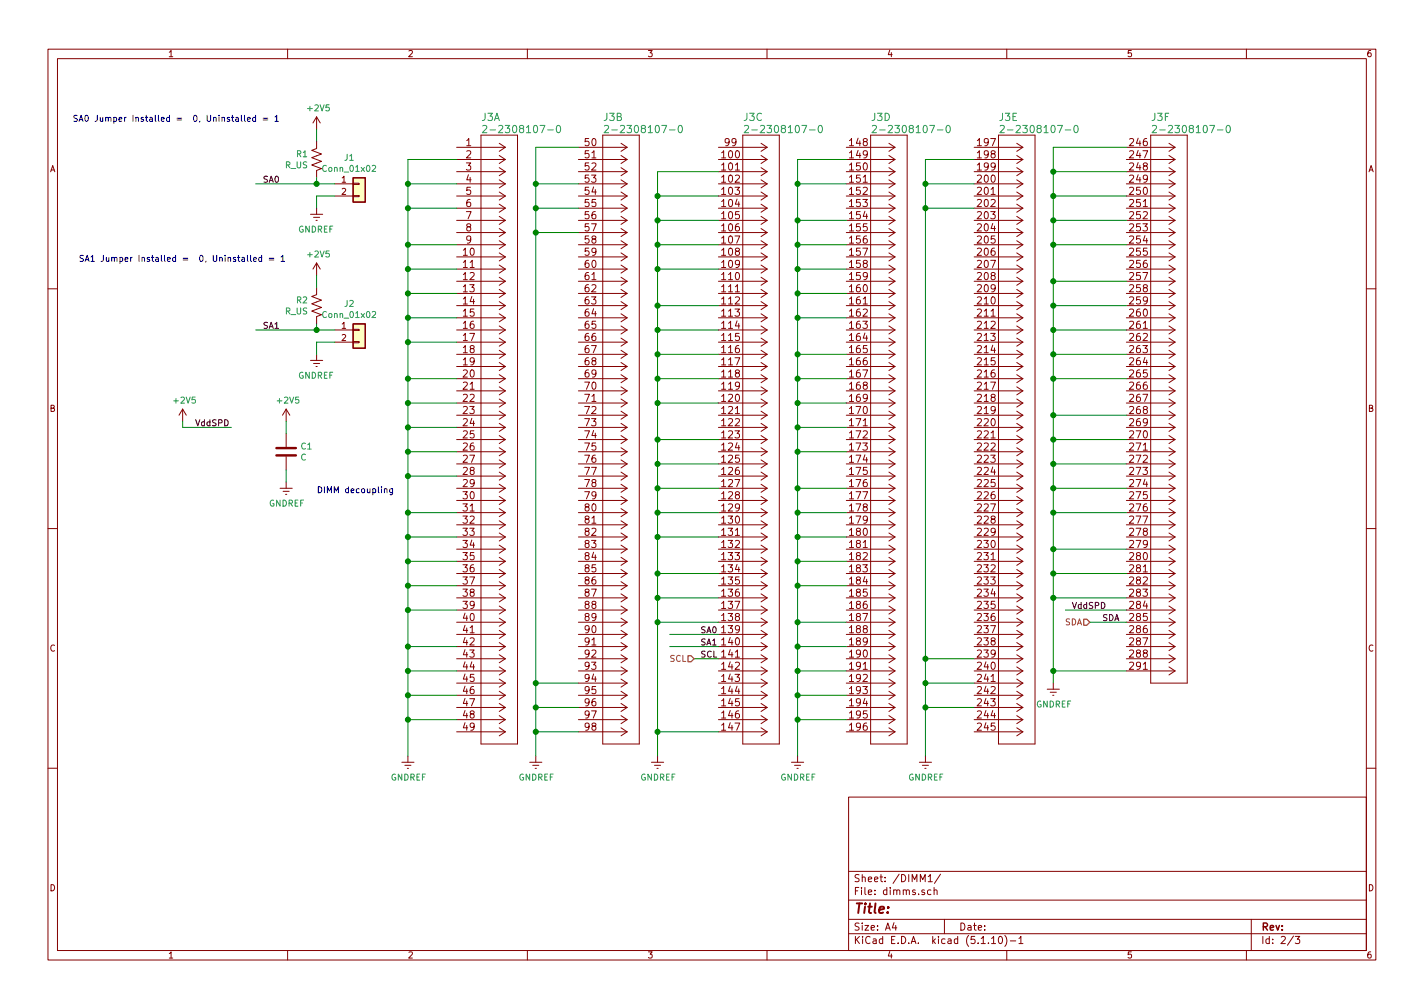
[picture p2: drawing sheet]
<svg xmlns="http://www.w3.org/2000/svg" width="297mm" height="210mm" viewBox="0 0 297 210" stroke-linecap="round" stroke-linejoin="round" font-family="sans-serif">
<defs><g id="words">
<text font-size="2.8" fill="#840000" x="178" y="190.5">Title:</text>
<g font-size="2.1" fill="#008484">
<text x="100.4" y="25.2">J3A</text>
<text x="102.8" y="27.8">2-2308107-0</text>
<text x="125.9" y="25.2">J3B</text>
<text x="128.2" y="27.8">2-2308107-0</text>
<text x="155.1" y="25.2">J3C</text>
<text x="157.4" y="27.8">2-2308107-0</text>
<text x="181.8" y="25.2">J3D</text>
<text x="184.1" y="27.8">2-2308107-0</text>
<text x="208.5" y="25.2">J3E</text>
<text x="210.7" y="27.8">2-2308107-0</text>
<text x="240.2" y="25.2">J3F</text>
<text x="242.5" y="27.8">2-2308107-0</text>
</g>
<g font-size="2.1" fill="#840000">
<text x="97.2" y="30.5">1</text>
<text x="97.2" y="33">2</text>
<text x="97.2" y="35.6">3</text>
<text x="122" y="30.5">50</text>
<text x="122" y="33">51</text>
<text x="122" y="35.6">52</text>
<text x="150.7" y="33">100</text>
<text x="150.7" y="35.6">101</text>
<text x="151.3" y="30.5">99</text>
<text x="177.3" y="30.5">148</text>
<text x="177.3" y="33">149</text>
<text x="177.3" y="35.6">150</text>
<text x="204" y="30.5">197</text>
<text x="204" y="33">198</text>
<text x="204" y="35.6">199</text>
<text x="235.8" y="30.5">246</text>
<text x="235.8" y="33">247</text>
<text x="235.8" y="35.6">248</text>
<text x="97.2" y="38.1">4</text>
<text x="97.2" y="40.6">5</text>
<text x="122" y="38.1">53</text>
<text x="122" y="40.6">54</text>
<text x="150.7" y="38.1">102</text>
<text x="150.7" y="40.6">103</text>
<text x="177.3" y="38.1">151</text>
<text x="177.3" y="40.6">152</text>
<text x="204" y="38.1">200</text>
<text x="204" y="40.6">201</text>
<text x="235.8" y="38.1">249</text>
<text x="235.8" y="40.6">250</text>
<text x="97.2" y="43.2">6</text>
<text x="97.2" y="45.7">7</text>
<text x="122" y="43.2">55</text>
<text x="122" y="45.7">56</text>
<text x="150.7" y="43.2">104</text>
<text x="150.7" y="45.7">105</text>
<text x="177.3" y="43.2">153</text>
<text x="177.3" y="45.7">154</text>
<text x="204" y="43.2">202</text>
<text x="204" y="45.7">203</text>
<text x="235.8" y="43.2">251</text>
<text x="235.8" y="45.7">252</text>
<text x="96.6" y="53.3">10</text>
<text x="97.2" y="48.3">8</text>
<text x="97.2" y="50.8">9</text>
<text x="122" y="48.3">57</text>
<text x="122" y="50.8">58</text>
<text x="122" y="53.3">59</text>
<text x="150.7" y="48.3">106</text>
<text x="150.7" y="50.8">107</text>
<text x="150.7" y="53.3">108</text>
<text x="177.3" y="48.3">155</text>
<text x="177.3" y="50.8">156</text>
<text x="177.3" y="53.3">157</text>
<text x="204" y="48.3">204</text>
<text x="204" y="50.8">205</text>
<text x="204" y="53.3">206</text>
<text x="235.8" y="48.3">253</text>
<text x="235.8" y="50.8">254</text>
<text x="235.8" y="53.3">255</text>
<text x="96.6" y="55.9">11</text>
<text x="96.6" y="58.4">12</text>
<text x="122" y="55.9">60</text>
<text x="122" y="58.4">61</text>
<text x="150.7" y="55.9">109</text>
<text x="150.7" y="58.4">110</text>
<text x="177.3" y="55.9">158</text>
<text x="177.3" y="58.4">159</text>
<text x="204" y="55.9">207</text>
<text x="204" y="58.4">208</text>
<text x="235.8" y="55.9">256</text>
<text x="235.8" y="58.4">257</text>
<text x="96.6" y="61">13</text>
<text x="96.6" y="63.5">14</text>
<text x="122" y="61">62</text>
<text x="122" y="63.5">63</text>
<text x="150.7" y="61">111</text>
<text x="150.7" y="63.5">112</text>
<text x="177.3" y="61">160</text>
<text x="177.3" y="63.5">161</text>
<text x="204" y="61">209</text>
<text x="204" y="63.5">210</text>
<text x="235.8" y="61">258</text>
<text x="235.8" y="63.5">259</text>
<text x="96.6" y="66">15</text>
<text x="96.6" y="68.6">16</text>
<text x="96.6" y="71.1">17</text>
<text x="122" y="66">64</text>
<text x="122" y="68.6">65</text>
<text x="122" y="71.1">66</text>
<text x="150.7" y="66">113</text>
<text x="150.7" y="68.6">114</text>
<text x="150.7" y="71.1">115</text>
<text x="177.3" y="66">162</text>
<text x="177.3" y="68.6">163</text>
<text x="177.3" y="71.1">164</text>
<text x="204" y="66">211</text>
<text x="204" y="68.6">212</text>
<text x="204" y="71.1">213</text>
<text x="235.8" y="66">260</text>
<text x="235.8" y="68.6">261</text>
<text x="235.8" y="71.1">262</text>
<text x="96.6" y="73.7">18</text>
<text x="96.6" y="76.2">19</text>
<text x="122" y="73.7">67</text>
<text x="122" y="76.2">68</text>
<text x="150.7" y="73.7">116</text>
<text x="150.7" y="76.2">117</text>
<text x="177.3" y="73.7">165</text>
<text x="177.3" y="76.2">166</text>
<text x="204" y="73.7">214</text>
<text x="204" y="76.2">215</text>
<text x="235.8" y="73.7">263</text>
<text x="235.8" y="76.2">264</text>
<text x="96.6" y="78.7">20</text>
<text x="96.6" y="81.3">21</text>
<text x="96.6" y="83.8">22</text>
<text x="122" y="78.7">69</text>
<text x="122" y="81.3">70</text>
<text x="122" y="83.8">71</text>
<text x="150.7" y="78.7">118</text>
<text x="150.7" y="81.3">119</text>
<text x="150.7" y="83.8">120</text>
<text x="177.3" y="78.7">167</text>
<text x="177.3" y="81.3">168</text>
<text x="177.3" y="83.8">169</text>
<text x="204" y="78.7">216</text>
<text x="204" y="81.3">217</text>
<text x="204" y="83.8">218</text>
<text x="235.8" y="78.7">265</text>
<text x="235.8" y="81.3">266</text>
<text x="235.8" y="83.8">267</text>
<text x="96.6" y="86.4">23</text>
<text x="96.6" y="88.9">24</text>
<text x="122" y="86.4">72</text>
<text x="122" y="88.9">73</text>
<text x="150.7" y="86.4">121</text>
<text x="150.7" y="88.9">122</text>
<text x="177.3" y="86.4">170</text>
<text x="177.3" y="88.9">171</text>
<text x="204" y="86.4">219</text>
<text x="204" y="88.9">220</text>
<text x="235.8" y="86.4">268</text>
<text x="235.8" y="88.9">269</text>
<text x="96.6" y="91.4">25</text>
<text x="96.6" y="94">26</text>
<text x="122" y="91.4">74</text>
<text x="122" y="94">75</text>
<text x="150.7" y="91.4">123</text>
<text x="150.7" y="94">124</text>
<text x="177.3" y="91.4">172</text>
<text x="177.3" y="94">173</text>
<text x="204" y="91.4">221</text>
<text x="204" y="94">222</text>
<text x="235.8" y="91.4">270</text>
<text x="235.8" y="94">271</text>
<text x="96.6" y="96.5">27</text>
<text x="96.6" y="99.1">28</text>
<text x="96.6" y="101.6">29</text>
<text x="122" y="96.5">76</text>
<text x="122" y="99.1">77</text>
<text x="122" y="101.6">78</text>
<text x="150.7" y="96.5">125</text>
<text x="150.7" y="99.1">126</text>
<text x="150.7" y="101.6">127</text>
<text x="177.3" y="96.5">174</text>
<text x="177.3" y="99.1">175</text>
<text x="177.3" y="101.6">176</text>
<text x="204" y="96.5">223</text>
<text x="204" y="99.1">224</text>
<text x="204" y="101.6">225</text>
<text x="235.8" y="96.5">272</text>
<text x="235.8" y="99.1">273</text>
<text x="235.8" y="101.6">274</text>
<text x="96.6" y="104.1">30</text>
<text x="96.6" y="106.7">31</text>
<text x="122" y="104.1">79</text>
<text x="122" y="106.7">80</text>
<text x="150.7" y="104.1">128</text>
<text x="150.7" y="106.7">129</text>
<text x="177.3" y="104.1">177</text>
<text x="177.3" y="106.7">178</text>
<text x="204" y="104.1">226</text>
<text x="204" y="106.7">227</text>
<text x="235.8" y="104.1">275</text>
<text x="235.8" y="106.7">276</text>
<text x="96.6" y="109.2">32</text>
<text x="96.6" y="111.8">33</text>
<text x="122" y="109.2">81</text>
<text x="122" y="111.8">82</text>
<text x="150.7" y="109.2">130</text>
<text x="150.7" y="111.8">131</text>
<text x="177.3" y="109.2">179</text>
<text x="177.3" y="111.8">180</text>
<text x="204" y="109.2">228</text>
<text x="204" y="111.8">229</text>
<text x="235.8" y="109.2">277</text>
<text x="235.8" y="111.8">278</text>
<text x="96.6" y="114.3">34</text>
<text x="96.6" y="116.8">35</text>
<text x="96.6" y="119.4">36</text>
<text x="122" y="114.3">83</text>
<text x="122" y="116.8">84</text>
<text x="122" y="119.4">85</text>
<text x="150.7" y="114.3">132</text>
<text x="150.7" y="116.8">133</text>
<text x="150.7" y="119.4">134</text>
<text x="177.3" y="114.3">181</text>
<text x="177.3" y="116.8">182</text>
<text x="177.3" y="119.4">183</text>
<text x="204" y="114.3">230</text>
<text x="204" y="116.8">231</text>
<text x="204" y="119.4">232</text>
<text x="235.8" y="114.3">279</text>
<text x="235.8" y="116.8">280</text>
<text x="235.8" y="119.4">281</text>
<text x="96.6" y="121.9">37</text>
<text x="96.6" y="124.5">38</text>
<text x="122" y="121.9">86</text>
<text x="122" y="124.5">87</text>
<text x="150.7" y="121.9">135</text>
<text x="150.7" y="124.5">136</text>
<text x="177.3" y="121.9">184</text>
<text x="177.3" y="124.5">185</text>
<text x="204" y="121.9">233</text>
<text x="204" y="124.5">234</text>
<text x="235.8" y="121.9">282</text>
<text x="235.8" y="124.5">283</text>
<text x="96.6" y="127">39</text>
<text x="96.6" y="129.5">40</text>
<text x="122" y="127">88</text>
<text x="122" y="129.5">89</text>
<text x="150.7" y="127">137</text>
<text x="150.7" y="129.5">138</text>
<text x="177.3" y="127">186</text>
<text x="177.3" y="129.5">187</text>
<text x="204" y="127">235</text>
<text x="204" y="129.5">236</text>
<text x="235.8" y="127">284</text>
<text x="235.8" y="129.5">285</text>
<text x="96.6" y="132.1">41</text>
<text x="96.6" y="134.6">42</text>
<text x="96.6" y="137.2">43</text>
<text x="122" y="132.1">90</text>
<text x="122" y="134.6">91</text>
<text x="122" y="137.2">92</text>
<text x="150.7" y="132.1">139</text>
<text x="150.7" y="134.6">140</text>
<text x="150.7" y="137.2">141</text>
<text x="177.3" y="132.1">188</text>
<text x="177.3" y="134.6">189</text>
<text x="177.3" y="137.2">190</text>
<text x="204" y="132.1">237</text>
<text x="204" y="134.6">238</text>
<text x="204" y="137.2">239</text>
<text x="235.8" y="132.1">286</text>
<text x="235.8" y="134.6">287</text>
<text x="235.8" y="137.2">288</text>
<text x="96.6" y="139.7">44</text>
<text x="96.6" y="142.2">45</text>
<text x="122" y="139.7">93</text>
<text x="122" y="142.2">94</text>
<text x="150.7" y="139.7">142</text>
<text x="150.7" y="142.2">143</text>
<text x="177.3" y="139.7">191</text>
<text x="177.3" y="142.2">192</text>
<text x="204" y="139.7">240</text>
<text x="204" y="142.2">241</text>
<text x="235.8" y="139.7">291</text>
<text x="96.6" y="144.8">46</text>
<text x="96.6" y="147.3">47</text>
<text x="96.6" y="149.9">48</text>
<text x="122" y="144.8">95</text>
<text x="122" y="147.3">96</text>
<text x="122" y="149.9">97</text>
<text x="150.7" y="144.8">144</text>
<text x="150.7" y="147.3">145</text>
<text x="150.7" y="149.9">146</text>
<text x="177.3" y="144.8">193</text>
<text x="177.3" y="147.3">194</text>
<text x="177.3" y="149.9">195</text>
<text x="204" y="144.8">242</text>
<text x="204" y="147.3">243</text>
<text x="204" y="149.9">244</text>
<text x="96.6" y="152.4">49</text>
<text x="122" y="152.4">98</text>
<text x="150.7" y="152.4">147</text>
<text x="177.3" y="152.4">196</text>
<text x="204" y="152.4">245</text>
<text x="178" y="184">Sheet: /DIMM1/</text>
<text x="178" y="186.7">File: dimms.sch</text>
<text x="178" y="196.9">KiCad E.D.A. kicad (5.1.10)-1</text>
<text x="178" y="194.1">Size: A4</text>
<text x="200" y="194.1">Date:</text>
<text x="263" y="194.1">Rev:</text>
<text x="263" y="196.9">Id: 2/3</text>
</g>
<g font-size="1.8" fill="#840000">
<text x="35" y="11.9">1</text>
<text x="85" y="11.9">2</text>
<text x="135" y="11.9">3</text>
<text x="185" y="11.9">4</text>
<text x="235" y="11.9">5</text>
<text x="285" y="11.9">6</text>
<text x="10.4" y="35.9">A</text>
<text x="285.4" y="35.9">A</text>
<text x="71.3" y="38.1">1</text>
<text x="71.3" y="40.6">2</text>
<text x="71.3" y="68.6">1</text>
<text x="71.3" y="71.1">2</text>
<text x="10.4" y="85.9">B</text>
<text x="285.4" y="85.9">B</text>
<text x="10.4" y="135.9">C</text>
<text x="285.4" y="135.9">C</text>
<text x="10.4" y="185.9">D</text>
<text x="285.4" y="185.9">D</text>
<text x="35" y="199.9">1</text>
<text x="85" y="199.9">2</text>
<text x="135" y="199.9">3</text>
<text x="185" y="199.9">4</text>
<text x="235" y="199.9">5</text>
<text x="285" y="199.9">6</text>
</g>
<g font-size="1.8" fill="#008484">
<text x="64.3" y="23.2">+2V5</text>
<text x="59.5" y="35.1">R_US</text>
<text x="61.9" y="32.8">R1</text>
<text x="67.6" y="35.8">Conn_01x02</text>
<text x="71.9" y="33.5">J1</text>
<text x="62.2" y="48.5">GNDREF</text>
<text x="64.3" y="53.7">+2V5</text>
<text x="59.5" y="65.6">R_US</text>
<text x="61.9" y="63.3">R2</text>
<text x="71.9" y="64">J2</text>
<text x="67.6" y="66.3">Conn_01x02</text>
<text x="62.2" y="79">GNDREF</text>
<text x="36.4" y="84.2">+2V5</text>
<text x="58" y="84.2">+2V5</text>
<text x="62.8" y="93.7">C1</text>
<text x="62.7" y="96.1">C</text>
<text x="56.1" y="105.7">GNDREF</text>
<text x="216.1" y="147.6">GNDREF</text>
<text x="81.5" y="162.8">GNDREF</text>
<text x="108.2" y="162.8">GNDREF</text>
<text x="133.6" y="162.8">GNDREF</text>
<text x="162.8" y="162.8">GNDREF</text>
<text x="189.4" y="162.8">GNDREF</text>
</g>
<g font-size="1.8" fill="#0000c2">
<text x="23.4" y="25.4">SA0 Jumper Installed = 0, Uninstalled = 1</text>
<text x="24.7" y="54.6">SA1 Jumper Installed = 0, Uninstalled = 1</text>
<text x="66" y="102.9">DIMM decoupling</text>
</g>
<g font-size="1.8">
<text x="55" y="38.1">SA0</text>
<text x="55" y="68.6">SA1</text>
<text x="40.6" y="88.9">VddSPD</text>
<text x="223.5" y="127">VddSPD</text>
<text x="229.9" y="129.5">SDA</text>
<text x="146" y="132.1">SA0</text>
<text x="146" y="134.6">SA1</text>
<text x="146" y="137.2">SCL</text>
</g>
<g font-size="1.8" fill="#848400">
<text x="222.1" y="130.4">SDA</text>
<text x="139.7" y="138">SCL</text>
</g>
</g></defs>
<g fill="none" stroke="#840000" stroke-width=".21">
<path d="M10 10.3h277v189.9h-277zM12 12.2h273v186.1h-273zM60 10.3v1.9M110 10.3v1.9M160 10.3v1.9M210 10.3v1.9M260 10.3v1.9M66 29.5v1.5l-1 .4 2.1 .7-2.1 .8 2.1 .7-2.1 .8 2.1 .8-1.1 .4v1.5M66 24.4v2.5M66 24.4l-.7 1.2M66 24.4l.8 1.2M69.8 38.3h3.9"/>
<path d="M73.7 38.2h1.2v.3h-1.2zM95.2 30.7h10.2M95.2 33.3h10.2M95.2 35.8h10.2M95.2 38.3h10.2M100.3 28.2h7.6v127h-7.6zM104.1 29.9l1.3 .8M104.1 32.4l1.3 .9M104.1 35l1.3 .8M104.1 37.5l1.3 .8M105.4 30.7l-1.3 .9M105.4 33.3l-1.3 .8"/>
<path d="M105.4 35.8l-1.3 .8M105.4 38.3l-1.3 .9M120.6 30.7h10.2M120.6 33.3h10.2M120.6 35.8h10.2M120.6 38.3h10.2M125.7 28.2h7.6v127h-7.6zM129.5 29.9l1.3 .8M129.5 32.4l1.3 .9M129.5 35l1.3 .8M129.5 37.5l1.3 .8M130.8 30.7l-1.3 .9"/>
<path d="M130.8 33.3l-1.3 .8M130.8 35.8l-1.3 .8M130.8 38.3l-1.3 .9M149.9 30.7h10.1M149.9 33.3h10.1M149.9 35.8h10.1M149.9 38.3h10.1M154.9 28.2h7.7v127h-7.7zM158.7 29.9l1.3 .8M158.7 32.4l1.3 .9M158.7 35l1.3 .8M158.7 37.5l1.3 .8"/>
<path d="M160 30.7l-1.3 .9M160 33.3l-1.3 .8M160 35.8l-1.3 .8M160 38.3l-1.3 .9M176.5 30.7h10.2M176.5 33.3h10.2M176.5 35.8h10.2M176.5 38.3h10.2M181.6 28.2h7.6v127h-7.6zM185.4 29.9l1.3 .8M185.4 32.4l1.3 .9M185.4 35l1.3 .8"/>
<path d="M185.4 37.5l1.3 .8M186.7 30.7l-1.3 .9M186.7 33.3l-1.3 .8M186.7 35.8l-1.3 .8M186.7 38.3l-1.3 .9M203.2 30.7h10.2M203.2 33.3h10.2M203.2 35.8h10.2M203.2 38.3h10.2M208.3 28.2h7.6v127h-7.6zM212.1 29.9l1.3 .8M212.1 32.4l1.3 .9"/>
<path d="M212.1 35l1.3 .8M212.1 37.5l1.3 .8M213.4 30.7l-1.3 .9M213.4 33.3l-1.3 .8M213.4 35.8l-1.3 .8M213.4 38.3l-1.3 .9M234.9 30.7h10.2M234.9 33.3h10.2M234.9 35.8h10.2M234.9 38.3h10.2M240 28.2h7.6v114.3h-7.6zM243.8 29.9l1.3 .8"/>
<path d="M243.8 32.4l1.3 .9M243.8 35l1.3 .8M243.8 37.5l1.3 .8M245.1 30.7l-1.3 .9M245.1 33.3l-1.3 .8M245.1 35.8l-1.3 .8M245.1 38.3l-1.3 .9M64.8 44.7h2.5M65.4 45.3h1.3M65.9 46h.3M66 59.9v1.6l-1 .3 2.1 .8-2.1 .8 2.1 .7-2.1 .8 2.1 .8-1.1 .3v1.6M66 43.4v1.3"/>
<path d="M66 54.9v2.5M66 54.9l-.7 1.2M66 54.9l.8 1.2M69.8 40.9h3.9M73.7 40.8h1.2v.2h-1.2zM95.2 40.9h10.2M95.2 43.4h10.2M95.2 46h10.2M95.2 48.5h10.2M95.2 51h10.2M95.2 53.6h10.2M95.2 56.1h10.2"/>
<path d="M95.2 58.7h10.2M104.1 40.1l1.3 .8M104.1 42.6l1.3 .8M104.1 45.1l1.3 .9M104.1 47.7l1.3 .8M104.1 50.2l1.3 .8M104.1 52.8l1.3 .8M104.1 55.3l1.3 .8M104.1 57.8l1.3 .9M105.4 40.9l-1.3 .8M105.4 43.4l-1.3 .9M105.4 46l-1.3 .8"/>
<path d="M105.4 48.5l-1.3 .8M105.4 51l-1.3 .9M105.4 53.6l-1.3 .8M105.4 56.1l-1.3 .9M105.4 58.7l-1.3 .8M120.6 40.9h10.2M120.6 43.4h10.2M120.6 46h10.2M120.6 48.5h10.2M120.6 51h10.2M120.6 53.6h10.2M120.6 56.1h10.2"/>
<path d="M120.6 58.7h10.2M129.5 40.1l1.3 .8M129.5 42.6l1.3 .8M129.5 45.1l1.3 .9M129.5 47.7l1.3 .8M129.5 50.2l1.3 .8M129.5 52.8l1.3 .8M129.5 55.3l1.3 .8M129.5 57.8l1.3 .9M130.8 40.9l-1.3 .8M130.8 43.4l-1.3 .9M130.8 46l-1.3 .8"/>
<path d="M130.8 48.5l-1.3 .8M130.8 51l-1.3 .9M130.8 53.6l-1.3 .8M130.8 56.1l-1.3 .9M130.8 58.7l-1.3 .8M149.9 40.9h10.1M149.9 43.4h10.1M149.9 46h10.1M149.9 48.5h10.1M149.9 51h10.1M149.9 53.6h10.1M149.9 56.1h10.1"/>
<path d="M149.9 58.7h10.1M158.7 40.1l1.3 .8M158.7 42.6l1.3 .8M158.7 45.1l1.3 .9M158.7 47.7l1.3 .8M158.7 50.2l1.3 .8M158.7 52.8l1.3 .8M158.7 55.3l1.3 .8M158.7 57.8l1.3 .9M160 40.9l-1.3 .8M160 43.4l-1.3 .9M160 46l-1.3 .8"/>
<path d="M160 48.5l-1.3 .8M160 51l-1.3 .9M160 53.6l-1.3 .8M160 56.1l-1.3 .9M160 58.7l-1.3 .8M176.5 40.9h10.2M176.5 43.4h10.2M176.5 46h10.2M176.5 48.5h10.2M176.5 51h10.2M176.5 53.6h10.2M176.5 56.1h10.2"/>
<path d="M176.5 58.7h10.2M185.4 40.1l1.3 .8M185.4 42.6l1.3 .8M185.4 45.1l1.3 .9M185.4 47.7l1.3 .8M185.4 50.2l1.3 .8M185.4 52.8l1.3 .8M185.4 55.3l1.3 .8M185.4 57.8l1.3 .9M186.7 40.9l-1.3 .8M186.7 43.4l-1.3 .9M186.7 46l-1.3 .8"/>
<path d="M186.7 48.5l-1.3 .8M186.7 51l-1.3 .9M186.7 53.6l-1.3 .8M186.7 56.1l-1.3 .9M186.7 58.7l-1.3 .8M203.2 40.9h10.2M203.2 43.4h10.2M203.2 46h10.2M203.2 48.5h10.2M203.2 51h10.2M203.2 53.6h10.2M203.2 56.1h10.2"/>
<path d="M203.2 58.7h10.2M212.1 40.1l1.3 .8M212.1 42.6l1.3 .8M212.1 45.1l1.3 .9M212.1 47.7l1.3 .8M212.1 50.2l1.3 .8M212.1 52.8l1.3 .8M212.1 55.3l1.3 .8M212.1 57.8l1.3 .9M213.4 40.9l-1.3 .8M213.4 43.4l-1.3 .9M213.4 46l-1.3 .8"/>
<path d="M213.4 48.5l-1.3 .8M213.4 51l-1.3 .9M213.4 53.6l-1.3 .8M213.4 56.1l-1.3 .9M213.4 58.7l-1.3 .8M234.9 40.9h10.2M234.9 43.4h10.2M234.9 46h10.2M234.9 48.5h10.2M234.9 51h10.2M234.9 53.6h10.2M234.9 56.1h10.2"/>
<path d="M234.9 58.7h10.2M243.8 40.1l1.3 .8M243.8 42.6l1.3 .8M243.8 45.1l1.3 .9M243.8 47.7l1.3 .8M243.8 50.2l1.3 .8M243.8 52.8l1.3 .8M243.8 55.3l1.3 .8M243.8 57.8l1.3 .9M245.1 40.9l-1.3 .8M245.1 43.4l-1.3 .9M245.1 46l-1.3 .8"/>
<path d="M245.1 48.5l-1.3 .8M245.1 51l-1.3 .9M245.1 53.6l-1.3 .8M245.1 56.1l-1.3 .9M245.1 58.7l-1.3 .8M10 60.2h2M64.8 75.2h2.5M65.4 75.8h1.3M65.9 76.4h.3M66 73.9v1.3M69.8 68.8h3.9M69.8 71.4h3.9"/>
<path d="M73.7 71.2h1.2v.3h-1.2zM73.7 68.7h1.2v.3h-1.2zM95.2 61.2h10.2M95.2 63.7h10.2M95.2 66.3h10.2M95.2 68.8h10.2M95.2 71.4h10.2M95.2 73.9h10.2M95.2 76.4h10.2M95.2 79h10.2M104.1 60.4l1.3 .8M104.1 62.9l1.3 .8"/>
<path d="M104.1 65.5l1.3 .8M104.1 68l1.3 .8M104.1 70.5l1.3 .9M104.1 73.1l1.3 .8M104.1 75.6l1.3 .8M104.1 78.2l1.3 .8M105.4 61.2l-1.3 .8M105.4 63.7l-1.3 .9M105.4 66.3l-1.3 .8M105.4 68.8l-1.3 .9M105.4 71.4l-1.3 .8M105.4 73.9l-1.3 .8"/>
<path d="M105.4 76.4l-1.3 .9M105.4 79l-1.3 .8M120.6 61.2h10.2M120.6 63.7h10.2M120.6 66.3h10.2M120.6 68.8h10.2M120.6 71.4h10.2M120.6 73.9h10.2M120.6 76.4h10.2M120.6 79h10.2M129.5 60.4l1.3 .8M129.5 62.9l1.3 .8"/>
<path d="M129.5 65.5l1.3 .8M129.5 68l1.3 .8M129.5 70.5l1.3 .9M129.5 73.1l1.3 .8M129.5 75.6l1.3 .8M129.5 78.2l1.3 .8M130.8 61.2l-1.3 .8M130.8 63.7l-1.3 .9M130.8 66.3l-1.3 .8M130.8 68.8l-1.3 .9M130.8 71.4l-1.3 .8M130.8 73.9l-1.3 .8"/>
<path d="M130.8 76.4l-1.3 .9M130.8 79l-1.3 .8M149.9 61.2h10.1M149.9 63.7h10.1M149.9 66.3h10.1M149.9 68.8h10.1M149.9 71.4h10.1M149.9 73.9h10.1M149.9 76.4h10.1M149.9 79h10.1M158.7 60.4l1.3 .8M158.7 62.9l1.3 .8"/>
<path d="M158.7 65.5l1.3 .8M158.7 68l1.3 .8M158.7 70.5l1.3 .9M158.7 73.1l1.3 .8M158.7 75.6l1.3 .8M158.7 78.2l1.3 .8M160 61.2l-1.3 .8M160 63.7l-1.3 .9M160 66.3l-1.3 .8M160 68.8l-1.3 .9M160 71.4l-1.3 .8M160 73.9l-1.3 .8"/>
<path d="M160 76.4l-1.3 .9M160 79l-1.3 .8M176.5 61.2h10.2M176.5 63.7h10.2M176.5 66.3h10.2M176.5 68.8h10.2M176.5 71.4h10.2M176.5 73.9h10.2M176.5 76.4h10.2M176.5 79h10.2M185.4 60.4l1.3 .8M185.4 62.9l1.3 .8"/>
<path d="M185.4 65.5l1.3 .8M185.4 68l1.3 .8M185.4 70.5l1.3 .9M185.4 73.1l1.3 .8M185.4 75.6l1.3 .8M185.4 78.2l1.3 .8M186.7 61.2l-1.3 .8M186.7 63.7l-1.3 .9M186.7 66.3l-1.3 .8M186.7 68.8l-1.3 .9M186.7 71.4l-1.3 .8M186.7 73.9l-1.3 .8"/>
<path d="M186.7 76.4l-1.3 .9M186.7 79l-1.3 .8M203.2 61.2h10.2M203.2 63.7h10.2M203.2 66.3h10.2M203.2 68.8h10.2M203.2 71.4h10.2M203.2 73.9h10.2M203.2 76.4h10.2M203.2 79h10.2M212.1 60.4l1.3 .8M212.1 62.9l1.3 .8"/>
<path d="M212.1 65.5l1.3 .8M212.1 68l1.3 .8M212.1 70.5l1.3 .9M212.1 73.1l1.3 .8M212.1 75.6l1.3 .8M212.1 78.2l1.3 .8M213.4 61.2l-1.3 .8M213.4 63.7l-1.3 .9M213.4 66.3l-1.3 .8M213.4 68.8l-1.3 .9M213.4 71.4l-1.3 .8M213.4 73.9l-1.3 .8"/>
<path d="M213.4 76.4l-1.3 .9M213.4 79l-1.3 .8M234.9 61.2h10.2M234.9 63.7h10.2M234.9 66.3h10.2M234.9 68.8h10.2M234.9 71.4h10.2M234.9 73.9h10.2M234.9 76.4h10.2M234.9 79h10.2M243.8 60.4l1.3 .8M243.8 62.9l1.3 .8"/>
<path d="M243.8 65.5l1.3 .8M243.8 68l1.3 .8M243.8 70.5l1.3 .9M243.8 73.1l1.3 .8M243.8 75.6l1.3 .8M243.8 78.2l1.3 .8M245.1 61.2l-1.3 .8M245.1 63.7l-1.3 .9M245.1 66.3l-1.3 .8M245.1 68.8l-1.3 .9M245.1 71.4l-1.3 .8M245.1 73.9l-1.3 .8"/>
<path d="M245.1 76.4l-1.3 .9M245.1 79l-1.3 .8M285 60.2h2M38.1 85.3l-.8 1.3M38.1 85.3v2.6M38.1 85.3l.8 1.3M59.7 85.3v2.6M59.7 90.4v2.8M59.7 95.2v2.8M59.7 85.3l-.8 1.3M59.7 85.3l.8 1.3M95.2 81.5h10.2"/>
<path d="M95.2 84.1h10.2M95.2 86.6h10.2M95.2 89.1h10.2M95.2 91.7h10.2M95.2 94.2h10.2M95.2 96.8h10.2M95.2 99.3h10.2M104.1 80.7l1.3 .8M104.1 83.2l1.3 .9M104.1 85.8l1.3 .8M104.1 88.3l1.3 .8M104.1 90.9l1.3 .8"/>
<path d="M104.1 93.4l1.3 .8M104.1 95.9l1.3 .9M104.1 98.5l1.3 .8M105.4 81.5l-1.3 .9M105.4 84.1l-1.3 .8M105.4 86.6l-1.3 .8M105.4 89.1l-1.3 .9M105.4 91.7l-1.3 .8M105.4 94.2l-1.3 .9M105.4 96.8l-1.3 .8M105.4 99.3l-1.3 .8M120.6 81.5h10.2"/>
<path d="M120.6 84.1h10.2M120.6 86.6h10.2M120.6 89.1h10.2M120.6 91.7h10.2M120.6 94.2h10.2M120.6 96.8h10.2M120.6 99.3h10.2M129.5 80.7l1.3 .8M129.5 83.2l1.3 .9M129.5 85.8l1.3 .8M129.5 88.3l1.3 .8M129.5 90.9l1.3 .8"/>
<path d="M129.5 93.4l1.3 .8M129.5 95.9l1.3 .9M129.5 98.5l1.3 .8M130.8 81.5l-1.3 .9M130.8 84.1l-1.3 .8M130.8 86.6l-1.3 .8M130.8 89.1l-1.3 .9M130.8 91.7l-1.3 .8M130.8 94.2l-1.3 .9M130.8 96.8l-1.3 .8M130.8 99.3l-1.3 .8M149.9 81.5h10.1"/>
<path d="M149.9 84.1h10.1M149.9 86.6h10.1M149.9 89.1h10.1M149.9 91.7h10.1M149.9 94.2h10.1M149.9 96.8h10.1M149.9 99.3h10.1M158.7 80.7l1.3 .8M158.7 83.2l1.3 .9M158.7 85.8l1.3 .8M158.7 88.3l1.3 .8M158.7 90.9l1.3 .8"/>
<path d="M158.7 93.4l1.3 .8M158.7 95.9l1.3 .9M158.7 98.5l1.3 .8M160 81.5l-1.3 .9M160 84.1l-1.3 .8M160 86.6l-1.3 .8M160 89.1l-1.3 .9M160 91.7l-1.3 .8M160 94.2l-1.3 .9M160 96.8l-1.3 .8M160 99.3l-1.3 .8M176.5 81.5h10.2"/>
<path d="M176.5 84.1h10.2M176.5 86.6h10.2M176.5 89.1h10.2M176.5 91.7h10.2M176.5 94.2h10.2M176.5 96.8h10.2M176.5 99.3h10.2M185.4 80.7l1.3 .8M185.4 83.2l1.3 .9M185.4 85.8l1.3 .8M185.4 88.3l1.3 .8M185.4 90.9l1.3 .8"/>
<path d="M185.4 93.4l1.3 .8M185.4 95.9l1.3 .9M185.4 98.5l1.3 .8M186.7 81.5l-1.3 .9M186.7 84.1l-1.3 .8M186.7 86.6l-1.3 .8M186.7 89.1l-1.3 .9M186.7 91.7l-1.3 .8M186.7 94.2l-1.3 .9M186.7 96.8l-1.3 .8M186.7 99.3l-1.3 .8M203.2 81.5h10.2"/>
<path d="M203.2 84.1h10.2M203.2 86.6h10.2M203.2 89.1h10.2M203.2 91.7h10.2M203.2 94.2h10.2M203.2 96.8h10.2M203.2 99.3h10.2M212.1 80.7l1.3 .8M212.1 83.2l1.3 .9M212.1 85.8l1.3 .8M212.1 88.3l1.3 .8M212.1 90.9l1.3 .8"/>
<path d="M212.1 93.4l1.3 .8M212.1 95.9l1.3 .9M212.1 98.5l1.3 .8M213.4 81.5l-1.3 .9M213.4 84.1l-1.3 .8M213.4 86.6l-1.3 .8M213.4 89.1l-1.3 .9M213.4 91.7l-1.3 .8M213.4 94.2l-1.3 .9M213.4 96.8l-1.3 .8M213.4 99.3l-1.3 .8M234.9 81.5h10.2"/>
<path d="M234.9 84.1h10.2M234.9 86.6h10.2M234.9 89.1h10.2M234.9 91.7h10.2M234.9 94.2h10.2M234.9 96.8h10.2M234.9 99.3h10.2M243.8 80.7l1.3 .8M243.8 83.2l1.3 .9M243.8 85.8l1.3 .8M243.8 88.3l1.3 .8M243.8 90.9l1.3 .8"/>
<path d="M243.8 93.4l1.3 .8M243.8 95.9l1.3 .9M243.8 98.5l1.3 .8M245.1 81.5l-1.3 .9M245.1 84.1l-1.3 .8M245.1 86.6l-1.3 .8M245.1 89.1l-1.3 .9M245.1 91.7l-1.3 .8M245.1 94.2l-1.3 .9M245.1 96.8l-1.3 .8M245.1 99.3l-1.3 .8M10 110.3h2"/>
<path d="M58.4 101.8h2.6M59.1 102.5h1.2M59.6 103.1h.2M59.7 100.6v1.2M95.2 101.8h10.2M95.2 104.4h10.2M95.2 106.9h10.2M95.2 109.5h10.2M95.2 112h10.2M95.2 114.5h10.2M95.2 117.1h10.2M95.2 119.6h10.2"/>
<path d="M104.1 101l1.3 .8M104.1 103.6l1.3 .8M104.1 106.1l1.3 .8M104.1 108.6l1.3 .9M104.1 111.2l1.3 .8M104.1 113.7l1.3 .8M104.1 116.3l1.3 .8M104.1 118.8l1.3 .8M105.4 101.8l-1.3 .9M105.4 104.4l-1.3 .8M105.4 106.9l-1.3 .9M105.4 109.5l-1.3 .8"/>
<path d="M105.4 112l-1.3 .8M105.4 114.5l-1.3 .9M105.4 117.1l-1.3 .8M105.4 119.6l-1.3 .9M120.6 101.8h10.2M120.6 104.4h10.2M120.6 106.9h10.2M120.6 109.5h10.2M120.6 112h10.2M120.6 114.5h10.2M120.6 117.1h10.2M120.6 119.6h10.2"/>
<path d="M129.5 101l1.3 .8M129.5 103.6l1.3 .8M129.5 106.1l1.3 .8M129.5 108.6l1.3 .9M129.5 111.2l1.3 .8M129.5 113.7l1.3 .8M129.5 116.3l1.3 .8M129.5 118.8l1.3 .8M130.8 101.8l-1.3 .9M130.8 104.4l-1.3 .8M130.8 106.9l-1.3 .9M130.8 109.5l-1.3 .8"/>
<path d="M130.8 112l-1.3 .8M130.8 114.5l-1.3 .9M130.8 117.1l-1.3 .8M130.8 119.6l-1.3 .9M149.9 101.8h10.1M149.9 104.4h10.1M149.9 106.9h10.1M149.9 109.5h10.1M149.9 112h10.1M149.9 114.5h10.1M149.9 117.1h10.1M149.9 119.6h10.1"/>
<path d="M158.7 101l1.3 .8M158.7 103.6l1.3 .8M158.7 106.1l1.3 .8M158.7 108.6l1.3 .9M158.7 111.2l1.3 .8M158.7 113.7l1.3 .8M158.7 116.3l1.3 .8M158.7 118.8l1.3 .8M160 101.8l-1.3 .9M160 104.4l-1.3 .8M160 106.9l-1.3 .9M160 109.5l-1.3 .8"/>
<path d="M160 112l-1.3 .8M160 114.5l-1.3 .9M160 117.1l-1.3 .8M160 119.6l-1.3 .9M176.5 101.8h10.2M176.5 104.4h10.2M176.5 106.9h10.2M176.5 109.5h10.2M176.5 112h10.2M176.5 114.5h10.2M176.5 117.1h10.2M176.5 119.6h10.2"/>
<path d="M185.4 101l1.3 .8M185.4 103.6l1.3 .8M185.4 106.1l1.3 .8M185.4 108.6l1.3 .9M185.4 111.2l1.3 .8M185.4 113.7l1.3 .8M185.4 116.3l1.3 .8M185.4 118.8l1.3 .8M186.7 101.8l-1.3 .9M186.7 104.4l-1.3 .8M186.7 106.9l-1.3 .9M186.7 109.5l-1.3 .8"/>
<path d="M186.7 112l-1.3 .8M186.7 114.5l-1.3 .9M186.7 117.1l-1.3 .8M186.7 119.6l-1.3 .9M203.2 101.8h10.2M203.2 104.4h10.2M203.2 106.9h10.2M203.2 109.5h10.2M203.2 112h10.2M203.2 114.5h10.2M203.2 117.1h10.2M203.2 119.6h10.2"/>
<path d="M212.1 101l1.3 .8M212.1 103.6l1.3 .8M212.1 106.1l1.3 .8M212.1 108.6l1.3 .9M212.1 111.2l1.3 .8M212.1 113.7l1.3 .8M212.1 116.3l1.3 .8M212.1 118.8l1.3 .8M213.4 101.8l-1.3 .9M213.4 104.4l-1.3 .8M213.4 106.9l-1.3 .9M213.4 109.5l-1.3 .8"/>
<path d="M213.4 112l-1.3 .8M213.4 114.5l-1.3 .9M213.4 117.1l-1.3 .8M213.4 119.6l-1.3 .9M234.9 101.8h10.2M234.9 104.4h10.2M234.9 106.9h10.2M234.9 109.5h10.2M234.9 112h10.2M234.9 114.5h10.2M234.9 117.1h10.2M234.9 119.6h10.2"/>
<path d="M243.8 101l1.3 .8M243.8 103.6l1.3 .8M243.8 106.1l1.3 .8M243.8 108.6l1.3 .9M243.8 111.2l1.3 .8M243.8 113.7l1.3 .8M243.8 116.3l1.3 .8M243.8 118.8l1.3 .8M245.1 101.8l-1.3 .9M245.1 104.4l-1.3 .8M245.1 106.9l-1.3 .9M245.1 109.5l-1.3 .8"/>
<path d="M245.1 112l-1.3 .8M245.1 114.5l-1.3 .9M245.1 117.1l-1.3 .8M245.1 119.6l-1.3 .9M285 110.3h2M95.2 122.2h10.2M95.2 124.7h10.2M95.2 127.2h10.2M95.2 129.8h10.2M95.2 132.3h10.2M95.2 134.9h10.2M95.2 137.4h10.2"/>
<path d="M95.2 139.9h10.2M104.1 121.3l1.3 .9M104.1 123.9l1.3 .8M104.1 126.4l1.3 .8M104.1 129l1.3 .8M104.1 131.5l1.3 .8M104.1 134l1.3 .9M104.1 136.6l1.3 .8M104.1 139.1l1.3 .8M105.4 122.2l-1.3 .8M105.4 124.7l-1.3 .8M105.4 127.2l-1.3 .9"/>
<path d="M105.4 129.8l-1.3 .8M105.4 132.3l-1.3 .9M105.4 134.9l-1.3 .8M105.4 137.4l-1.3 .8M105.4 139.9l-1.3 .9M120.6 122.2h10.2M120.6 124.7h10.2M120.6 127.2h10.2M120.6 129.8h10.2M120.6 132.3h10.2M120.6 134.9h10.2M120.6 137.4h10.2"/>
<path d="M120.6 139.9h10.2M129.5 121.3l1.3 .9M129.5 123.9l1.3 .8M129.5 126.4l1.3 .8M129.5 129l1.3 .8M129.5 131.5l1.3 .8M129.5 134l1.3 .9M129.5 136.6l1.3 .8M129.5 139.1l1.3 .8M130.8 122.2l-1.3 .8M130.8 124.7l-1.3 .8M130.8 127.2l-1.3 .9"/>
<path d="M130.8 129.8l-1.3 .8M130.8 132.3l-1.3 .9M130.8 134.9l-1.3 .8M130.8 137.4l-1.3 .8M130.8 139.9l-1.3 .9M149.9 122.2h10.1M149.9 124.7h10.1M149.9 127.2h10.1M149.9 129.8h10.1M149.9 132.3h10.1M149.9 134.9h10.1M149.9 137.4h10.1"/>
<path d="M149.9 139.9h10.1M158.7 121.3l1.3 .9M158.7 123.9l1.3 .8M158.7 126.4l1.3 .8M158.7 129l1.3 .8M158.7 131.5l1.3 .8M158.7 134l1.3 .9M158.7 136.6l1.3 .8M158.7 139.1l1.3 .8M160 122.2l-1.3 .8M160 124.7l-1.3 .8M160 127.2l-1.3 .9"/>
<path d="M160 129.8l-1.3 .8M160 132.3l-1.3 .9M160 134.9l-1.3 .8M160 137.4l-1.3 .8M160 139.9l-1.3 .9M176.5 122.2h10.2M176.5 124.7h10.2M176.5 127.2h10.2M176.5 129.8h10.2M176.5 132.3h10.2M176.5 134.9h10.2M176.5 137.4h10.2"/>
<path d="M176.5 139.9h10.2M185.4 121.3l1.3 .9M185.4 123.9l1.3 .8M185.4 126.4l1.3 .8M185.4 129l1.3 .8M185.4 131.5l1.3 .8M185.4 134l1.3 .9M185.4 136.6l1.3 .8M185.4 139.1l1.3 .8M186.7 122.2l-1.3 .8M186.7 124.7l-1.3 .8M186.7 127.2l-1.3 .9"/>
<path d="M186.7 129.8l-1.3 .8M186.7 132.3l-1.3 .9M186.7 134.9l-1.3 .8M186.7 137.4l-1.3 .8M186.7 139.9l-1.3 .9M203.2 122.2h10.2M203.2 124.7h10.2M203.2 127.2h10.2M203.2 129.8h10.2M203.2 132.3h10.2M203.2 134.9h10.2M203.2 137.4h10.2"/>
<path d="M203.2 139.9h10.2M212.1 121.3l1.3 .9M212.1 123.9l1.3 .8M212.1 126.4l1.3 .8M212.1 129l1.3 .8M212.1 131.5l1.3 .8M212.1 134l1.3 .9M212.1 136.6l1.3 .8M212.1 139.1l1.3 .8M213.4 122.2l-1.3 .8M213.4 124.7l-1.3 .8M213.4 127.2l-1.3 .9"/>
<path d="M213.4 129.8l-1.3 .8M213.4 132.3l-1.3 .9M213.4 134.9l-1.3 .8M213.4 137.4l-1.3 .8M213.4 139.9l-1.3 .9M234.9 122.2h10.2M234.9 124.7h10.2M234.9 127.2h10.2M234.9 129.8h10.2M234.9 132.3h10.2M234.9 134.9h10.2M234.9 137.4h10.2"/>
<path d="M234.9 139.9h10.2M243.8 121.3l1.3 .9M243.8 123.9l1.3 .8M243.8 126.4l1.3 .8M243.8 129l1.3 .8M243.8 131.5l1.3 .8M243.8 134l1.3 .9M243.8 136.6l1.3 .8M243.8 139.1l1.3 .8M245.1 122.2l-1.3 .8M245.1 124.7l-1.3 .8M245.1 127.2l-1.3 .9"/>
<path d="M245.1 129.8l-1.3 .8M245.1 132.3l-1.3 .9M245.1 134.9l-1.3 .8M245.1 137.4l-1.3 .8M245.1 139.9l-1.3 .9M83.8 159h2.6M84.5 159.6h1.2M85.1 157.7v1.3M95.2 145h10.2M95.2 142.5h10.2M95.2 147.6h10.2M95.2 150.1h10.2"/>
<path d="M95.2 152.6h10.2M104.1 141.7l1.3 .8M104.1 144.2l1.3 .8M104.1 146.7l1.3 .9M104.1 149.3l1.3 .8M104.1 151.8l1.3 .8M105.4 142.5l-1.3 .8M105.4 145l-1.3 .9M105.4 147.6l-1.3 .8M105.4 150.1l-1.3 .8M105.4 152.6l-1.3 .9M110.5 159h2.5"/>
<path d="M111.1 159.6h1.3M111.8 157.7v1.3M120.6 145h10.2M120.6 142.5h10.2M120.6 147.6h10.2M120.6 150.1h10.2M120.6 152.6h10.2M129.5 141.7l1.3 .8M129.5 144.2l1.3 .8M129.5 146.7l1.3 .9M129.5 149.3l1.3 .8M129.5 151.8l1.3 .8"/>
<path d="M130.8 142.5l-1.3 .8M130.8 145l-1.3 .9M130.8 147.6l-1.3 .8M130.8 150.1l-1.3 .8M130.8 152.6l-1.3 .9M135.9 159h2.5M136.5 159.6h1.3M137.2 157.7v1.3M149.9 145h10.1M149.9 142.5h10.1M149.9 147.6h10.1M149.9 150.1h10.1"/>
<path d="M149.9 152.6h10.1M158.7 141.7l1.3 .8M158.7 144.2l1.3 .8M158.7 146.7l1.3 .9M158.7 149.3l1.3 .8M158.7 151.8l1.3 .8M160 142.5l-1.3 .8M160 145l-1.3 .9M160 147.6l-1.3 .8M160 150.1l-1.3 .8M160 152.6l-1.3 .9M165.1 159h2.5"/>
<path d="M165.7 159.6h1.3M166.4 157.7v1.3M176.5 145h10.2M176.5 142.5h10.2M176.5 147.6h10.2M176.5 150.1h10.2M176.5 152.6h10.2M185.4 141.7l1.3 .8M185.4 144.2l1.3 .8M185.4 146.7l1.3 .9M185.4 149.3l1.3 .8M185.4 151.8l1.3 .8"/>
<path d="M186.7 142.5l-1.3 .8M186.7 145l-1.3 .9M186.7 147.6l-1.3 .8M186.7 150.1l-1.3 .8M186.7 152.6l-1.3 .9M191.8 159h2.5M192.4 159.6h1.3M193 157.7v1.3M203.2 145h10.2M203.2 142.5h10.2M203.2 147.6h10.2M203.2 150.1h10.2"/>
<path d="M203.2 152.6h10.2M212.1 141.7l1.3 .8M212.1 144.2l1.3 .8M212.1 146.7l1.3 .9M212.1 149.3l1.3 .8M212.1 151.8l1.3 .8M213.4 142.5l-1.3 .8M213.4 145l-1.3 .9M213.4 147.6l-1.3 .8M213.4 150.1l-1.3 .8M213.4 152.6l-1.3 .9M218.4 143.8h2.6"/>
<path d="M219.1 144.4h1.2M219.6 145h.2M219.7 142.5v1.3M10 160.2h2M85 160.3h.2M111.6 160.3h.3M137 160.3h.3M166.2 160.3h.3M177 166.3h108v32h-108zM192.9 160.3h.3M285 160.2h2M60 198.3v1.9"/>
<path d="M110 198.3v1.9M160 198.3v1.9M177 194.8h108M177 191.8h108M177 187.8h108M177 181.8h108M186.5 192.5l-.4 1h1M186.8 193v1M193.6 182.8l.5-.4v1.5M193.6 183.9h.9M194.2 185.7l-.4-.1-.3 .3v.6l.3 .1 .4-.1M194.8 185.7l.2-.1 .4 .1 .1 .9"/>
<path d="M194.8 185.1v1.5M196.2 182.3l-1.3 2M197 191.8v3M206.8 195.8l.5-.5v1.5M206.8 196.8h.9M208.5 195.4l.1-.1a.8 .8 0 0 1 .5 .8 .8 .8 0 0 1-.5 .7 1 1 0 0 1-.1-1.4zM209.6 195.1a1.71 1.71 0 0 1 0 2.3M210 198.3v1.9M210.7 196.3h1.2M212.5 195.8l.5-.5v1.5M212.5 196.8h.9M260 198.3v1.9"/>
<path d="M261 191.8v6.5M269.8 195.2l-1.2 2M270.2 195.3h.9l-.5 .6 .4 .1v.7l-.2 .1-.6-.1"/>
</g>
<g fill="none" stroke="#008484" stroke-width=".21">
<path d="M77.6 34.6l.5-.1 .3 .3-.8 1h.8M100.7 26.3l.5-.1 .3 .1v.3l-.9 1.1h.9M116.2 26.3l.2-.1a.81 .81 0 0 1 .6 .7 .81 .81 0 0 1-.6 .8l-.2-.2-.1-.4zM126.1 26.3l.5-.1 .3 .1v.3l-.9 1.1h.9M141.6 26.3l.2-.1a.81 .81 0 0 1 .6 .7 .81 .81 0 0 1-.6 .8l-.2-.2-.1-.4zM155.3 26.3l.6-.1 .2 .1 .1 .3-1 1.1h1M170.8 26.3l.2-.1a.81 .81 0 0 1 .6 .7 .81 .81 0 0 1-.6 .8l-.2-.2-.1-.4zM182 26.3l.5-.1 .3 .1v.3l-.9 1.1h.9M197.5 26.3l.2-.1a.81 .81 0 0 1 .5 .7 .81 .81 0 0 1-.5 .8l-.2-.2-.2-.4zM208.6 26.3l.6-.1 .2 .1 .1 .3-.9 1.1h.9M224.2 26.3l.2-.1a.81 .81 0 0 1 .5 .7 .81 .81 0 0 1-.5 .8l-.2-.2-.2-.4zM240.4 26.3l.5-.1 .3 .1v.3l-.9 1.1h.9"/>
<path d="M255.9 26.3l.2-.1a.81 .81 0 0 1 .6 .7 .81 .81 0 0 1-.6 .8l-.2-.2-.1-.4zM77.6 65.1l.5-.1 .3 .3-.8 .9h.8"/>
</g>
<g fill="#ffffc2" stroke="#ffffc2" stroke-width=".21">
<path d="M73.7 37.1h2.5v5.1h-2.5z"/>
<path d="M73.7 67.6h2.5v5h-2.5z"/>
</g>
<path d="M73.7 37.1h2.5v5.1h-2.5zM73.7 67.6h2.5v5h-2.5z" fill="none" stroke="#840000" stroke-width=".25"/>
<path d="M57.7 95h4M57.7 93.5h4" fill="none" stroke="#840000" stroke-width=".51"/>
<g fill="none" stroke="#008400" stroke-width=".21">
<path d="M53.3 38.3h16.5M66 26.9v2.6M66 37.1v1.2M85.1 38.3h10.1M95.2 33.3h-10.1v124.4M111.8 38.3h8.8M120.6 30.7h-8.8v127M149.9 35.8h-12.7v121.9M166.4 38.3h10.1M176.5 33.3h-10.1v124.4M193 38.3h10.2M203.2 33.3h-10.2v124.4"/>
<path d="M219.7 35.8h15.2M234.9 30.7h-15.2v111.8M66 57.4v2.5M69.8 40.9h-3.8v2.5M85.1 43.4h10.1M85.1 51h10.1M85.1 56.1h10.1M111.8 43.4h8.8M111.8 48.5h8.8M137.2 51h12.7M137.2 56.1h12.7M137.2 40.9h12.7"/>
<path d="M137.2 46h12.7M166.4 51h10.1M166.4 56.1h10.1M166.4 46h10.1M193 43.4h10.2M219.7 51h15.2M219.7 40.9h15.2M219.7 46h15.2M219.7 58.7h15.2M53.3 68.8h16.5M66 67.6v1.2M69.8 71.4h-3.8v2.5"/>
<path d="M85.1 71.4h10.1M85.1 61.2h10.1M85.1 66.3h10.1M85.1 79h10.1M137.2 68.8h12.7M137.2 79h12.7M137.2 73.9h12.7M137.2 63.7h12.7M166.4 61.2h10.1M166.4 66.3h10.1M166.4 79h10.1M166.4 73.9h10.1"/>
<path d="M219.7 68.8h15.2M219.7 79h15.2M219.7 73.9h15.2M219.7 63.7h15.2M38.1 87.9v1.2h10.2M59.7 87.9v2.5M59.7 98v2.6M85.1 89.1h10.1M85.1 84.1h10.1M85.1 94.2h10.1M85.1 99.3h10.1M137.2 96.8h12.7"/>
<path d="M137.2 84.1h12.7M137.2 91.7h12.7M166.4 89.1h10.1M166.4 84.1h10.1M166.4 94.2h10.1M219.7 96.8h15.2M219.7 91.7h15.2M219.7 86.6h15.2M85.1 106.9h10.1M85.1 112h10.1M85.1 117.1h10.1M137.2 119.6h12.7"/>
<path d="M137.2 101.8h12.7M137.2 106.9h12.7M137.2 112h12.7M166.4 101.8h10.1M166.4 106.9h10.1M166.4 112h10.1M166.4 117.1h10.1M219.7 119.6h15.2M219.7 114.5h15.2M219.7 101.8h15.2M219.7 106.9h15.2M85.1 139.9h10.1"/>
<path d="M85.1 134.9h10.1M85.1 127.2h10.1M85.1 122.2h10.1M137.2 129.8h12.7M137.2 124.7h12.7M139.7 132.3h10.2M139.7 134.9h10.2M144.8 137.4h5.1M166.4 139.9h10.1M166.4 134.9h10.1M166.4 129.8h10.1M166.4 122.2h10.1"/>
<path d="M193 137.4h10.2M219.7 139.9h15.2M219.7 124.7h15.2M222.2 127.2h12.7M227.3 129.8h7.6M85.1 145h10.1M85.1 150.1h10.1M111.8 152.6h8.8M111.8 147.6h8.8M111.8 142.5h8.8M137.2 152.6h12.7M166.4 145h10.1"/>
<path d="M166.4 150.1h10.1M193 147.6h10.2M193 142.5h10.2"/>
</g>
<path d="M143.5 136.8h.6l.7 .6-.7 .6h-.6zM226.1 129.2h.6l.6 .6-.6 .6h-.6z" fill="none" stroke="#848400" stroke-width=".25"/>
<g fill="none" stroke="#0000c2" stroke-width=".21">
<path d="M16.1 24.1l-.5-.1-.2 .2v.3l.6 .3 .1 .3-.2 .2h-.5M16.5 25.3l.4-1.3 .4 1.3M16.6 25h.6M17.8 24.2l.2-.2a.67 .67 0 0 1 .4 .7 .67 .67 0 0 1-.4 .6l-.3-.5zM20.3 24l-.1 1.1-.4 .2M20.9 24.5l.1 .8 .4-.1M21.4 24.5v.8M22 24.6l.5-.1 .1 .8M22 24.5v.8M22.6 24.7l.2-.2h.3v.8M57.4 24.4l.3-.4v1.3M57.4 25.3h.7"/>
<path d="M17.4 53.3h-.5l-.2 .1v.3l.6 .3 .1 .3-.3 .2h-.4M17.8 54.5l.4-1.2 .4 1.2M17.9 54.2h.6M19 53.6l.3-.3v1.2M19 54.5h.7M21.6 53.3l-.1 1.1-.4 .1M22.2 53.7v.8l.5-.1M22.7 53.7v.8M23.3 53.8l.5-.1 .1 .8M23.3 53.7v.8M23.9 53.9l.2-.2h.2l.1 .8M58.6 53.6l.4-.3v1.2"/>
<path d="M58.6 54.5h.8M80.2 102.1l.5-.1v.8M81.9 101.9l-.1 1.2-.2 .1-.2-.1M81.9 102l-.4-.1-.2 .3 .1 .5h.5"/>
</g>
<g fill="#008400" stroke="#008400" stroke-width=".25">
<circle cx="193" cy="142.5" r=".51"/>
<circle cx="137.2" cy="79" r=".51"/>
<circle cx="137.2" cy="68.8" r=".51"/>
<circle cx="219.7" cy="35.8" r=".51"/>
<circle cx="137.2" cy="73.9" r=".51"/>
<circle cx="85.1" cy="150.1" r=".51"/>
<circle cx="166.4" cy="38.3" r=".51"/>
<circle cx="137.2" cy="63.7" r=".51"/>
<circle cx="219.7" cy="91.7" r=".51"/>
<circle cx="219.7" cy="51" r=".51"/>
<circle cx="193" cy="147.6" r=".51"/>
<circle cx="137.2" cy="56.1" r=".51"/>
<circle cx="111.8" cy="48.5" r=".51"/>
<circle cx="111.8" cy="152.6" r=".51"/>
<circle cx="111.8" cy="147.6" r=".51"/>
<circle cx="219.7" cy="79" r=".51"/>
<circle cx="111.8" cy="142.5" r=".51"/>
<circle cx="137.2" cy="129.8" r=".51"/>
<circle cx="219.7" cy="73.9" r=".51"/>
<circle cx="137.2" cy="124.7" r=".51"/>
<circle cx="137.2" cy="40.9" r=".51"/>
<circle cx="219.7" cy="68.8" r=".51"/>
<circle cx="137.2" cy="119.6" r=".51"/>
<circle cx="219.7" cy="63.7" r=".51"/>
<circle cx="137.2" cy="112" r=".51"/>
<circle cx="219.7" cy="40.9" r=".51"/>
<circle cx="137.2" cy="46" r=".51"/>
<circle cx="219.7" cy="58.7" r=".51"/>
<circle cx="137.2" cy="106.9" r=".51"/>
<circle cx="111.8" cy="43.4" r=".51"/>
<circle cx="137.2" cy="101.8" r=".51"/>
<circle cx="85.1" cy="122.2" r=".51"/>
<circle cx="137.2" cy="96.8" r=".51"/>
<circle cx="137.2" cy="51" r=".51"/>
<circle cx="219.7" cy="46" r=".51"/>
<circle cx="137.2" cy="91.7" r=".51"/>
<circle cx="111.8" cy="38.3" r=".51"/>
<circle cx="137.2" cy="84.1" r=".51"/>
<circle cx="85.1" cy="43.4" r=".51"/>
<circle cx="85.1" cy="79" r=".51"/>
<circle cx="66" cy="38.3" r=".51"/>
<circle cx="85.1" cy="71.4" r=".51"/>
<circle cx="166.4" cy="122.2" r=".51"/>
<circle cx="85.1" cy="66.3" r=".51"/>
<circle cx="166.4" cy="117.1" r=".51"/>
<circle cx="85.1" cy="61.2" r=".51"/>
<circle cx="166.4" cy="66.3" r=".51"/>
<circle cx="219.7" cy="114.5" r=".51"/>
<circle cx="85.1" cy="56.1" r=".51"/>
<circle cx="166.4" cy="112" r=".51"/>
<circle cx="85.1" cy="51" r=".51"/>
<circle cx="166.4" cy="106.9" r=".51"/>
<circle cx="166.4" cy="129.8" r=".51"/>
<circle cx="166.4" cy="73.9" r=".51"/>
<circle cx="85.1" cy="38.3" r=".51"/>
<circle cx="166.4" cy="101.8" r=".51"/>
<circle cx="66" cy="68.8" r=".51"/>
<circle cx="166.4" cy="94.2" r=".51"/>
<circle cx="166.4" cy="79" r=".51"/>
<circle cx="219.7" cy="139.9" r=".51"/>
<circle cx="219.7" cy="124.7" r=".51"/>
<circle cx="166.4" cy="89.1" r=".51"/>
<circle cx="137.2" cy="152.6" r=".51"/>
<circle cx="166.4" cy="84.1" r=".51"/>
<circle cx="219.7" cy="119.6" r=".51"/>
<circle cx="85.1" cy="112" r=".51"/>
<circle cx="193" cy="137.4" r=".51"/>
<circle cx="85.1" cy="139.9" r=".51"/>
<circle cx="166.4" cy="46" r=".51"/>
<circle cx="85.1" cy="134.9" r=".51"/>
<circle cx="193" cy="43.4" r=".51"/>
<circle cx="85.1" cy="127.2" r=".51"/>
<circle cx="219.7" cy="96.8" r=".51"/>
<circle cx="219.7" cy="86.6" r=".51"/>
<circle cx="193" cy="38.3" r=".51"/>
<circle cx="85.1" cy="117.1" r=".51"/>
<circle cx="219.7" cy="101.8" r=".51"/>
<circle cx="166.4" cy="150.1" r=".51"/>
<circle cx="85.1" cy="145" r=".51"/>
<circle cx="166.4" cy="51" r=".51"/>
<circle cx="85.1" cy="106.9" r=".51"/>
<circle cx="166.4" cy="145" r=".51"/>
<circle cx="219.7" cy="106.9" r=".51"/>
<circle cx="85.1" cy="99.3" r=".51"/>
<circle cx="166.4" cy="139.9" r=".51"/>
<circle cx="85.1" cy="94.2" r=".51"/>
<circle cx="166.4" cy="56.1" r=".51"/>
<circle cx="85.1" cy="89.1" r=".51"/>
<circle cx="166.4" cy="134.9" r=".51"/>
<circle cx="85.1" cy="84.1" r=".51"/>
<circle cx="166.4" cy="61.2" r=".51"/>
</g>
<use href="#words"/>
</svg>
